VERSION 5.8 ;
BUSBITCHARS "[]" ;
DIVIDERCHAR "/" ;
CLEARANCEMEASURE EUCLIDEAN ;

SITE coresite_DH_P
    SIZE 0.0450 BY 0.2880 ;
    CLASS CORE ;
    SYMMETRY X Y ;
END coresite_DH_P

SITE coresite_DH_N
    SIZE 0.0450 BY 0.2880 ;
    CLASS CORE ;
    SYMMETRY X Y ;
END coresite_DH_N

SITE coresite
    SIZE 0.0450 BY 0.1440 ;
    CLASS CORE ;
    SYMMETRY X Y ;
END coresite

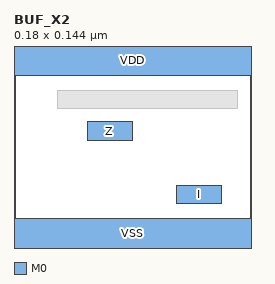
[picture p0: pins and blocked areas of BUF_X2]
MACRO BUF_X2
  CLASS CORE ;
  ORIGIN 0 0 ;
  FOREIGN BUF_X2 0 0 ;
  SIZE 0.1800 BY 0.1440 ;
  SYMMETRY X Y ;
  SITE coresite ;
  PIN I
    DIRECTION INPUT ;
    USE SIGNAL ;
    PORT
      LAYER M0 ;
        RECT 0.1230 0.0430 0.1575 0.0290 ;
    END
  END I
  PIN Z
    DIRECTION OUTPUT ;
    USE SIGNAL ;
    PORT
      LAYER M0 ;
        RECT 0.0555 0.0910 0.0900 0.0770 ;
    END
  END Z
  PIN VDD
    DIRECTION INOUT ;
    USE POWER ;
    SHAPE ABUTMENT ;
    PORT
      LAYER M0 ;
        RECT 0.0000 0.1260 0.1800 0.1620 ;
    END
  END VDD
  PIN VSS
    DIRECTION INOUT ;
    USE GROUND ;
    SHAPE ABUTMENT ;
    PORT
      LAYER M0 ;
        RECT 0.0000 -0.0180 0.1800 0.0180 ;
    END
  END VSS
  OBS
      LAYER M0 ;
        RECT 0.0330 0.1010 0.1695 0.1150 ;
  END
END BUF_X2

END LIBRARY
